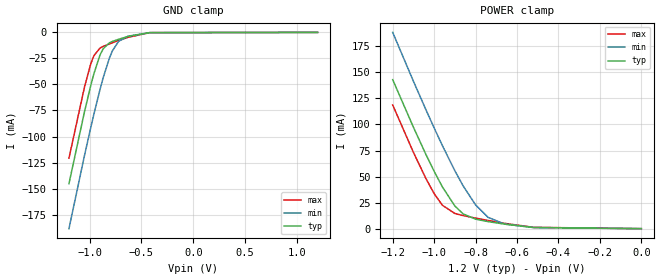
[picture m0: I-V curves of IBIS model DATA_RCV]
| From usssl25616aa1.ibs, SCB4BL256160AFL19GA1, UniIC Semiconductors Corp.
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|   Model DATA_RCV
[Model]  DATA_RCV
Model_type Input
Polarity   Non-Inverting
Enable   Active-High
Vinl =   0.3800V
Vinh =   0.8200V
C_comp   1.7430pF   1.7110pF   1.7640pF
[Temperature Range]   25.0000   0.1250k   -40.0000
[Voltage Range]   1.2000V   1.1400V   1.3000V
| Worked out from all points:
|   GND clamp passes 1 mA (typ) near -0.50 V on its own axis
|   POWER clamp passes 1 mA (typ) near -0.51 V on its own axis
[GND_clamp]
|Voltage   I(typ)   I(min)   I(max)
-1.2V     -145.3mA   -188.5mA   -120.8mA
-1.05V    -76.2mA    -118.2mA   -52.43mA
-990mV    -51.2mA    -91.62mA   -30.39mA
-960mV    -39.9mA    -78.82mA   -22.48mA
-900mV    -21.67mA   -54.7mA    -15mA
-870mV    -15.78mA   -43.66mA   -13.45mA
-810mV    -10.04mA   -24.79mA   -11.07mA
-780mV    -8.658mA   -17.59mA   -9.958mA
-720mV    -6.57mA    -8.545mA   -7.793mA
-630mV    -3.906mA   -3.64mA    -4.741mA
-420mV    -215.4uA   -240.5uA   -235uA
1.2V      1.597nA    22.84nA    1.463nA
[POWER_clamp]
|Voltage   I(typ)   I(min)   I(max)
-1.2V     143mA      188.4mA    118.7mA
-1.1V     97.38mA    141.5mA    73.24mA
-1.04V    71.38mA    114.3mA    48.22mA
-1V       55.04mA    96.69mA    33.64mA
-960mV    40mA       79.65mA    22.42mA
-900mV    21.75mA    55.6mA     14.58mA
-860mV    14.17mA    41.05mA    12.52mA
-800mV    9.133mA    22.79mA    10.12mA
-740mV    6.786mA    10.88mA    7.886mA
-660mV    4.332mA    4.436mA    5.101mA
-520mV    1.103mA    1.063mA    1.274mA
0V        1.597nA    6.003nA    2.16nA
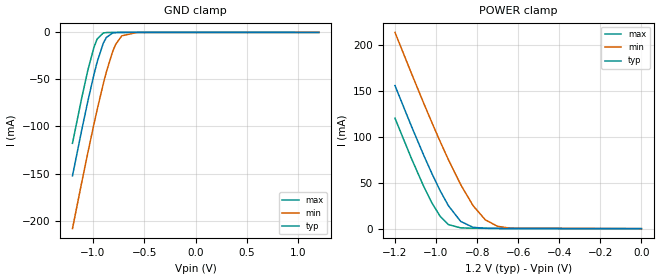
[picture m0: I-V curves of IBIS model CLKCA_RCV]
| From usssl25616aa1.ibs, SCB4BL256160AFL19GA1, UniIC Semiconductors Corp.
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|   Model CLKCA_RCV
[Model]  CLKCA_RCV
Model_type Input
Polarity   Non-Inverting
Enable   Active-High
Vinl =   0.3800V
Vinh =   0.8200V
C_comp   1.2950pF   1.2730pF   1.3120pF
[Temperature Range]   25.0000   0.1250k   -40.0000
[Voltage Range]   1.2000V   1.1400V   1.3000V
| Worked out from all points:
|   GND clamp passes 1 mA (typ) near -0.82 V on its own axis
|   POWER clamp passes 1 mA (typ) near -0.80 V on its own axis
[GND_clamp]
|Voltage   I(typ)   I(min)   I(max)
-1.2V     -152.5mA   -208.6mA   -117.9mA
-1.11V    -103.8mA   -159.5mA   -69.65mA
-1.05V    -72.94mA   -127.7mA   -40.07mA
-990mV    -44.4mA    -97.1mA    -15.51mA
-960mV    -31.61mA   -82.36mA   -7.11mA
-900mV    -11.47mA   -54.65mA   -660.1uA
-870mV    -5.396mA   -42.04mA   -162.2uA
-810mV    -752.5uA   -20.74mA   -9.166uA
-780mV    -251.2uA   -12.84mA   -2.167uA
-720mV    -26.67uA   -3.626mA   -121.2nA
-570mV    -94.94nA   -62.57uA   -235.2pA
1.2V      454.1pA    974.6pA    490.2pA
[POWER_clamp]
|Voltage   I(typ)   I(min)   I(max)
-1.2V     156.1mA    214.1mA    120.5mA
-1.12V    111.8mA    169.5mA    76.62mA
-1.06V    80.05mA    136.8mA    46.08mA
-1.02V    59.99mA    115.6mA    28.04mA
-980mV    41.4mA     95.05mA    13.46mA
-940mV    25.12mA    75.31mA    4.459mA
-880mV    7.896mA    48mA       846.4uA
-820mV    1.482mA    25.18mA    482.7uA
-760mV    394.4uA    9.579mA    358uA
-700mV    210.2uA    2.502mA    254.7uA
-640mV    132.1uA    564.6uA    165.1uA
0V        454.1pA    345.5pA    727.1pA
